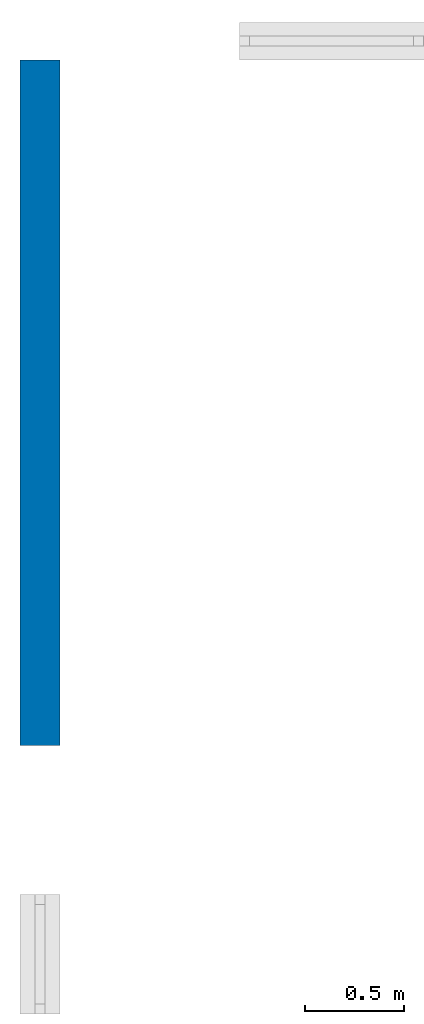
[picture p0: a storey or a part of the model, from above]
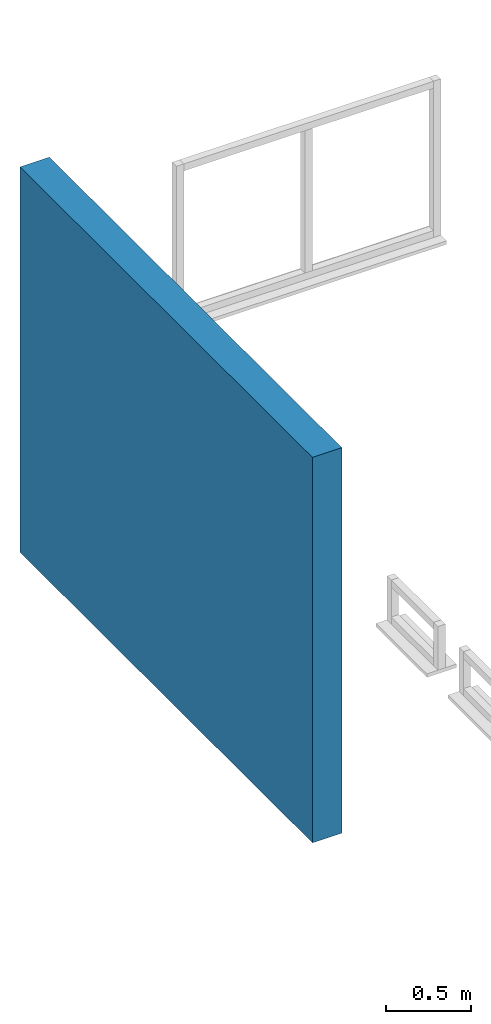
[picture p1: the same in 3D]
Properties of the parts of a building model (IFC2X3)

# File
Description: ViewDefinition [CoordinationView_V2.0]
File name: C:/Users/JEAN-P~1/AppData/Local/Temp/Lexocad20/maquette num enrichie.ifc
Time: 2016-04-22T13:54:12
Made in: Lexocad (64-Bit)

# IfcBuilding
LongName: Bâtiment

# IfcBuildingStorey (5)
Name | LongName | Elevation (m)
r+1 | r+1 | 2.7
r+3 | r+3 | 8.1
rdc | rdc | 0
r+2 | r+2 | 5.4
vs | vs | -0.85

# IfcBeam (2940)
In: vs
Name | Group
1482 x Bardage | Bardage
144 x Calage | Caillebotis
120 x Calage | Bardage
366 x Support bardage | Bardage
144 x Solive | Structure
90 x Sommier | Structure
54 x Poteau | Structure
48 x Ligneul | Structure
390 x Caillebotis | Caillebotis
102 x Contre-usinage

# IfcSlab (18)
PredefinedType: USERDEFINED
Name | In
6 x  | r+1
3 x  | rdc
6 x  | r+3
3 x  | r+2

# IfcWall (392)
Name | In
80 x  | vs
88 x  | rdc
57 x  | r+1
57 x  | r+2
rdc1 | rdc | Pset_Cadwork_Common - Group: mur r+2
12 x rdc1 | rdc | Pset_Cadwork_Common - Group: mur rdc
57 x  | r+3
10 x rdc1 | rdc | Pset_Cadwork_Common - Group: mur r+1
4 x  | rdc | Pset_Cadwork_Common - Group: murs rdc
7 x  | rdc | Pset_Cadwork_Common - Group: murs r+1
3 x rdc2 | rdc | Pset_Cadwork_Common - Group: murs r+1
3 x rdc entrée | rdc | Pset_Cadwork_Common - Group: murs rdc
4 x rdc2 | rdc | Pset_Cadwork_Common - Group: murs r+2
4 x rdc2 | rdc | Pset_Cadwork_Common - Group: murs r+3
rdc1 | rdc | Pset_Cadwork_Common - Group: mur r+3

3 x rdc3 | rdc | Pset_Cadwork_Common - Group: murs rdc

# IfcWindow (1000)
Name
88 x 
88 x leftFrame
21 x rightFrame | Pset_Cadwork_Common - Group: fenetre
88 x windowSill
88 x topFrame
60 x verticalBar
88 x bottomFrame
88 x rightFrame
21 x leftFrame | Pset_Cadwork_Common - Group: fenetre
21 x  | Pset_Cadwork_Common - Group: fenetre
21 x verticalBar | Pset_Cadwork_Common - Group: fenetre
38 x rightFrame | Pset_Cadwork_Common - Group: fenetres
38 x leftFrame | Pset_Cadwork_Common - Group: fenetres
38 x windowSill | Pset_Cadwork_Common - Group: fenetres
38 x topFrame | Pset_Cadwork_Common - Group: fenetres
38 x bottomFrame | Pset_Cadwork_Common - Group: fenetres
34 x verticalBar | Pset_Cadwork_Common - Group: fenetres
38 x  | Pset_Cadwork_Common - Group: fenetres
21 x windowSill | Pset_Cadwork_Common - Group: fenetre
21 x topFrame | Pset_Cadwork_Common - Group: fenetre
21 x bottomFrame | Pset_Cadwork_Common - Group: fenetre
3 x verticalLeftBar
